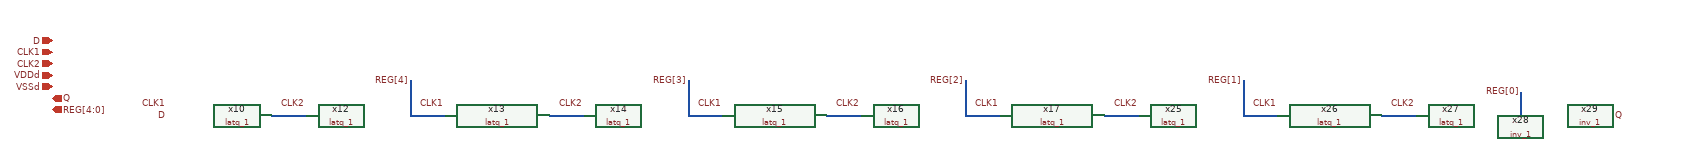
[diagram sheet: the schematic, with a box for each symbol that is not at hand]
v {xschem version=3.4.7 file_version=1.2}
G {}
K {}
V {}
S {}
E {}
N 480 -30 540 -30 {lab=#net1}
N 720 -50 720 -30 {lab=REG[4]}
N 720 -30 780 -30 {lab=REG[4]}
N 960 -30 1020 -30 {lab=#net2}
N 1200 -50 1200 -30 {lab=REG[3]}
N 1200 -30 1260 -30 {lab=REG[3]}
N 1440 -30 1500 -30 {lab=#net3}
N 1680 -50 1680 -30 {lab=REG[2]}
N 1680 -30 1740 -30 {lab=REG[2]}
N 1920 -30 1980 -30 {lab=#net4}
N 2160 -50 2160 -30 {lab=REG[1]}
N 2160 -30 2220 -30 {lab=REG[1]}
N 2400 -30 2460 -30 {lab=#net5}
N 2640 -70 2640 -30 {lab=REG[0]}
N 2160 -90 2160 -50 {lab=REG[1]}
N 1680 -90 1680 -50 {lab=REG[2]}
N 1200 -90 1200 -50 {lab=REG[3]}
N 720 -90 720 -50 {lab=REG[4]}
C {gf180mcu_fd_sc_mcu9t5v0_symbols/latq_1.sym} 390 -40 2 1 {name=x10 VGND=VSSd VNB=VDDd VPB=VSSd VPWR=VDDd prefix=gf180mcu_fd_sc_mcu9t5v0__ }
C {gf180mcu_fd_sc_mcu9t5v0_symbols/latq_1.sym} 630 -40 2 1 {name=x12 VGND=VSSd VNB=VDDd VPB=VSSd VPWR=VDDd prefix=gf180mcu_fd_sc_mcu9t5v0__ }
C {gf180mcu_fd_sc_mcu9t5v0_symbols/latq_1.sym} 870 -40 2 1 {name=x13 VGND=VSSd VNB=VDDd VPB=VSSd VPWR=VDDd prefix=gf180mcu_fd_sc_mcu9t5v0__ }
C {gf180mcu_fd_sc_mcu9t5v0_symbols/latq_1.sym} 1110 -40 2 1 {name=x14 VGND=VSSd VNB=VDDd VPB=VSSd VPWR=VDDd prefix=gf180mcu_fd_sc_mcu9t5v0__ }
C {gf180mcu_fd_sc_mcu9t5v0_symbols/latq_1.sym} 1350 -40 2 1 {name=x15 VGND=VSSd VNB=VDDd VPB=VSSd VPWR=VDDd prefix=gf180mcu_fd_sc_mcu9t5v0__ }
C {gf180mcu_fd_sc_mcu9t5v0_symbols/latq_1.sym} 1590 -40 2 1 {name=x16 VGND=VSSd VNB=VDDd VPB=VSSd VPWR=VDDd prefix=gf180mcu_fd_sc_mcu9t5v0__ }
C {gf180mcu_fd_sc_mcu9t5v0_symbols/latq_1.sym} 1830 -40 2 1 {name=x17 VGND=VSSd VNB=VDDd VPB=VSSd VPWR=VDDd prefix=gf180mcu_fd_sc_mcu9t5v0__ }
C {gf180mcu_fd_sc_mcu9t5v0_symbols/latq_1.sym} 2070 -40 2 1 {name=x25 VGND=VSSd VNB=VDDd VPB=VSSd VPWR=VDDd prefix=gf180mcu_fd_sc_mcu9t5v0__ }
C {gf180mcu_fd_sc_mcu9t5v0_symbols/latq_1.sym} 2310 -40 2 1 {name=x26 VGND=VSSd VNB=VDDd VPB=VSSd VPWR=VDDd prefix=gf180mcu_fd_sc_mcu9t5v0__ }
C {gf180mcu_fd_sc_mcu9t5v0_symbols/latq_1.sym} 2550 -40 2 1 {name=x27 VGND=VSSd VNB=VDDd VPB=VSSd VPWR=VDDd prefix=gf180mcu_fd_sc_mcu9t5v0__ }
C {lab_wire.sym} 300 -50 0 0 {name=p20 lab=CLK1}
C {lab_wire.sym} 540 -50 0 0 {name=p21 lab=CLK2}
C {lab_wire.sym} 780 -50 0 0 {name=p22 lab=CLK1}
C {lab_wire.sym} 1020 -50 0 0 {name=p23 lab=CLK2}
C {lab_wire.sym} 1260 -50 0 0 {name=p24 lab=CLK1}
C {lab_wire.sym} 1500 -50 0 0 {name=p25 lab=CLK2}
C {lab_wire.sym} 1740 -50 0 0 {name=p26 lab=CLK1}
C {lab_wire.sym} 1980 -50 0 0 {name=p27 lab=CLK2}
C {lab_wire.sym} 2220 -50 0 0 {name=p28 lab=CLK1}
C {lab_wire.sym} 2460 -50 0 0 {name=p29 lab=CLK2}
C {lab_wire.sym} 2800 -30 0 1 {name=p30 lab=Q}
C {lab_wire.sym} 300 -30 0 0 {name=p31 lab=D}
C {lab_wire.sym} 2640 -70 0 0 {name=p36 lab=REG[0]}
C {gf180mcu_fd_sc_mcu9t5v0_symbols/inv_1.sym} 2680 -30 0 0 {name=x28 VGND=VSSd VNB=VDDd VPB=VSSd VPWR=VDDd prefix=gf180mcu_fd_sc_mcu9t5v0__ }
C {gf180mcu_fd_sc_mcu9t5v0_symbols/inv_1.sym} 2760 -30 0 0 {name=x29 VGND=VSSd VNB=VDDd VPB=VSSd VPWR=VDDd prefix=gf180mcu_fd_sc_mcu9t5v0__ }
C {lab_wire.sym} 2160 -90 0 0 {name=p37 lab=REG[1]}
C {lab_wire.sym} 1680 -90 0 0 {name=p38 lab=REG[2]}
C {lab_wire.sym} 1200 -90 0 0 {name=p39 lab=REG[3]}
C {lab_wire.sym} 720 -90 0 0 {name=p40 lab=REG[4]}
C {ipin.sym} 100 -160 0 0 {name=p1 lab=D}
C {ipin.sym} 100 -140 0 0 {name=p2 lab=CLK1}
C {ipin.sym} 100 -120 0 0 {name=p3 lab=CLK2}
C {opin.sym} 100 -60 0 0 {name=p4 lab=Q}
C {opin.sym} 100 -40 0 0 {name=p5 lab=REG[4:0]}
C {ipin.sym} 100 -100 0 0 {name=p6 lab=VDDd}
C {ipin.sym} 100 -80 0 0 {name=p7 lab=VSSd}
